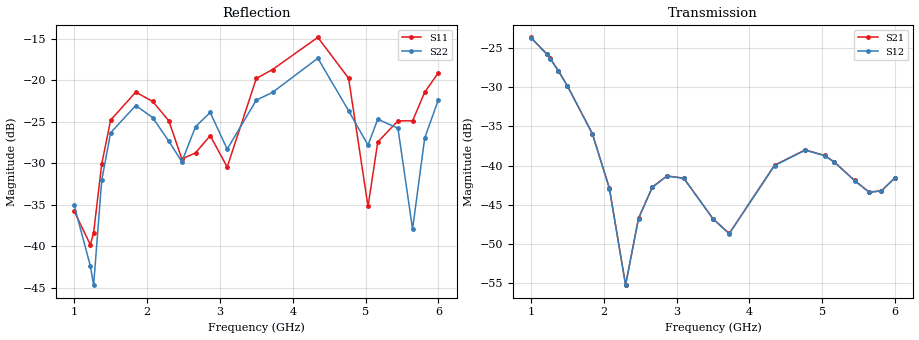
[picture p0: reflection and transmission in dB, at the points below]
!Agilent Technologies,E8364B,MY43040528,A.07.50.67
!Agilent E8364B: A.07.50.67
!Date: Sunday, March 01, 2026 21:13:16
!Correction: S11(Full 2 Port(1,2))
!S21(Full 2 Port(1,2))
!S12(Full 2 Port(1,2))
!S22(Full 2 Port(1,2))
!S2P File: Measurements: S11, S21, S12, S22:
# Hz S  dB  R 50
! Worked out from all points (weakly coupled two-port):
!   451 points, 1 GHz to 6 GHz, reference 50 ohm
!   highest |S21| = -23.66 dB at 1 GHz (marker M1); lowest = -55.2 dB at 2.3 GHz (marker M2)
!   lowest |S11| = -39.8 dB at 1.222 GHz (marker M3), VSWR 1.02, Z = 49.5 + j0.895 ohm
!   |S11| at or under -10 dB: start of sweep to end of sweep
!   |S22| runs from -45.1 to -17.0 dB; largest |S21 - S12| = 0.00024
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1e9  -35.79 58.6  -23.66 148.7  -23.69 148.7  -35.09 17.4
1.222222e9  -39.83 117.6  -25.81 20.3  -25.84 20.3  -42.39 35.2
1.266667e9  -38.35 146.2  -26.35 -5.3  -26.39 -5.2  -44.68 84.6
1.377778e9  -30.11 162.0  -27.91 -68.2  -27.94 -68.2  -32.06 107.7
1.5e9  -24.82 142.0  -29.81 -135.7  -29.83 -135.7  -26.34 78.8
1.844444e9  -21.45 81.8  -35.94 37.8  -35.96 37.9  -23.06 -0.7
2.077778e9  -22.57 53.2  -42.88 -85.2  -42.93 -85.1  -24.52 -37.8
2.3e9  -24.92 30.4  -55.21 -132.3  -55.24 -131.9  -27.37 -63.7
2.477778e9  -29.49 26.4  -46.71 -166.9  -46.75 -166.7  -29.82 -56.1
2.666667e9  -28.76 56.5  -42.74 96.1  -42.79 96.1  -25.59 -56.7
2.866667e9  -26.68 41.2  -41.32 -11.6  -41.34 -11.6  -23.90 -93.4
3.1e9  -30.47 57.9  -41.60 -138.5  -41.64 -138.5  -28.31 -115.4
3.5e9  -19.80 47.2  -46.78 22.6  -46.79 22.6  -22.41 -123.4
3.722222e9  -18.73 26.7  -48.65 -53.1  -48.71 -53.1  -21.48 -144.8
4.344444e9  -14.86 -44.5  -39.96 12.8  -40.00 12.8  -17.37 113.5
4.766667e9  -19.78 -110.1  -38.00 132.8  -38.04 132.8  -23.69 33.9
5.033333e9  -35.20 -86.9  -38.71 -25.8  -38.74 -25.8  -27.83 48.5
5.166667e9  -27.46 -42.2  -39.54 -106.8  -39.58 -106.8  -24.71 35.6
5.444444e9  -24.90 -67.5  -41.90 75.4  -41.93 75.3  -25.80 -28.6
5.644444e9  -24.91 -53.2  -43.38 -65.9  -43.41 -65.9  -37.95 -13.7
5.811111e9  -21.47 -54.2  -43.21 172.5  -43.24 172.6  -26.98 24.1
6e9  -19.10 -70.2  -41.53 41.4  -41.56 41.4  -22.34 -9.5
